VERSION 5.7 ;
  NOWIREEXTENSIONATPIN ON ;
  DIVIDERCHAR "/" ;
  BUSBITCHARS "[]" ;
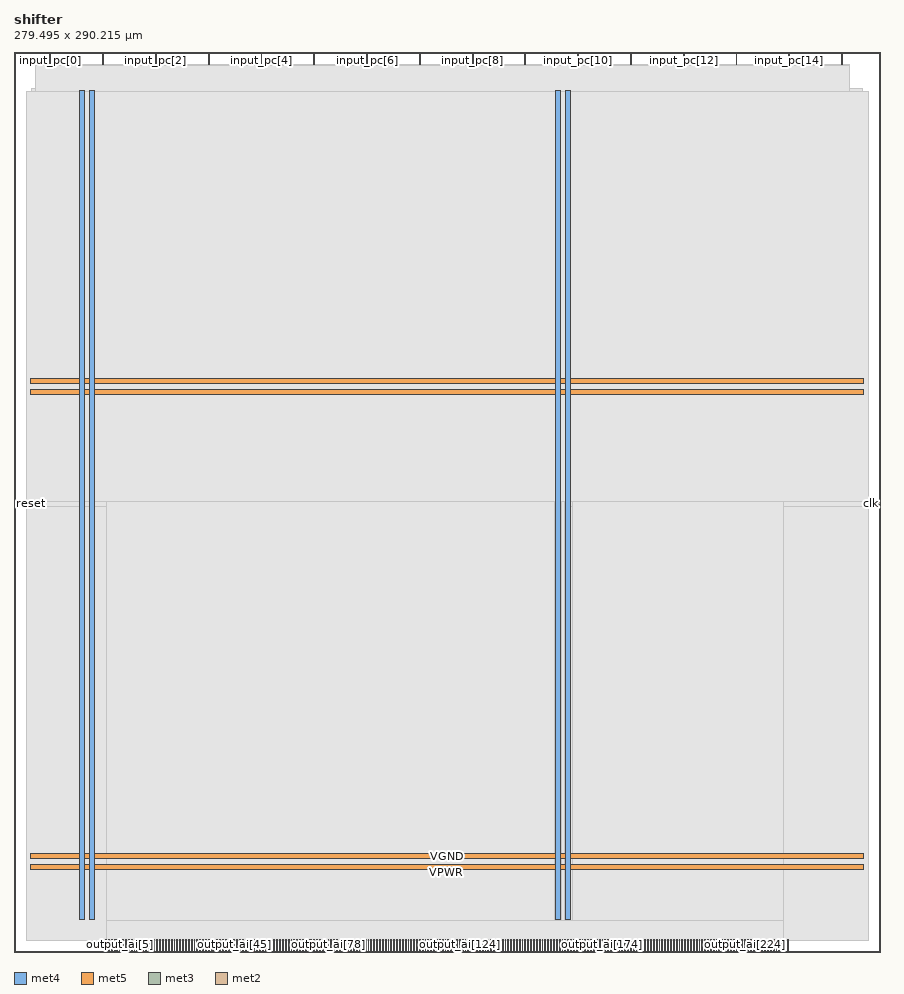
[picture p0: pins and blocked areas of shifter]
MACRO shifter
  CLASS BLOCK ;
  FOREIGN shifter ;
  ORIGIN 0.000 0.000 ;
  SIZE 279.495 BY 290.215 ;
  PIN VGND
    DIRECTION INOUT ;
    USE GROUND ;
    PORT
      LAYER met4 ;
        RECT 24.340 10.640 25.940 277.680 ;
    END
    PORT
      LAYER met4 ;
        RECT 177.940 10.640 179.540 277.680 ;
    END
    PORT
      LAYER met5 ;
        RECT 5.280 30.030 273.940 31.630 ;
    END
    PORT
      LAYER met5 ;
        RECT 5.280 183.210 273.940 184.810 ;
    END
  END VGND
  PIN VPWR
    DIRECTION INOUT ;
    USE POWER ;
    PORT
      LAYER met4 ;
        RECT 21.040 10.640 22.640 277.680 ;
    END
    PORT
      LAYER met4 ;
        RECT 174.640 10.640 176.240 277.680 ;
    END
    PORT
      LAYER met5 ;
        RECT 5.280 26.730 273.940 28.330 ;
    END
    PORT
      LAYER met5 ;
        RECT 5.280 179.910 273.940 181.510 ;
    END
  END VPWR
  PIN clk
    DIRECTION INPUT ;
    USE SIGNAL ;
    ANTENNAGATEAREA 0.852000 ;
    PORT
      LAYER met3 ;
        RECT 275.495 144.200 279.495 144.800 ;
    END
  END clk
  PIN input_pc[0]
    DIRECTION INPUT ;
    USE SIGNAL ;
    ANTENNAGATEAREA 0.213000 ;
    PORT
      LAYER met2 ;
        RECT 11.590 286.215 11.870 290.215 ;
    END
  END input_pc[0]
  PIN input_pc[10]
    DIRECTION INPUT ;
    USE SIGNAL ;
    ANTENNAGATEAREA 0.213000 ;
    PORT
      LAYER met2 ;
        RECT 181.790 286.215 182.070 290.215 ;
    END
  END input_pc[10]
  PIN input_pc[11]
    DIRECTION INPUT ;
    USE SIGNAL ;
    ANTENNAGATEAREA 0.196500 ;
    PORT
      LAYER met2 ;
        RECT 198.810 286.215 199.090 290.215 ;
    END
  END input_pc[11]
  PIN input_pc[12]
    DIRECTION INPUT ;
    USE SIGNAL ;
    ANTENNAGATEAREA 0.196500 ;
    PORT
      LAYER met2 ;
        RECT 215.830 286.215 216.110 290.215 ;
    END
  END input_pc[12]
  PIN input_pc[13]
    DIRECTION INPUT ;
    USE SIGNAL ;
    ANTENNAGATEAREA 0.196500 ;
    PORT
      LAYER met2 ;
        RECT 232.850 286.215 233.130 290.215 ;
    END
  END input_pc[13]
  PIN input_pc[14]
    DIRECTION INPUT ;
    USE SIGNAL ;
    ANTENNAGATEAREA 0.126000 ;
    PORT
      LAYER met2 ;
        RECT 249.870 286.215 250.150 290.215 ;
    END
  END input_pc[14]
  PIN input_pc[15]
    DIRECTION INPUT ;
    USE SIGNAL ;
    ANTENNAGATEAREA 0.126000 ;
    PORT
      LAYER met2 ;
        RECT 266.890 286.215 267.170 290.215 ;
    END
  END input_pc[15]
  PIN input_pc[1]
    DIRECTION INPUT ;
    USE SIGNAL ;
    ANTENNAGATEAREA 0.196500 ;
    PORT
      LAYER met2 ;
        RECT 28.610 286.215 28.890 290.215 ;
    END
  END input_pc[1]
  PIN input_pc[2]
    DIRECTION INPUT ;
    USE SIGNAL ;
    ANTENNAGATEAREA 0.126000 ;
    PORT
      LAYER met2 ;
        RECT 45.630 286.215 45.910 290.215 ;
    END
  END input_pc[2]
  PIN input_pc[3]
    DIRECTION INPUT ;
    USE SIGNAL ;
    ANTENNAGATEAREA 0.213000 ;
    PORT
      LAYER met2 ;
        RECT 62.650 286.215 62.930 290.215 ;
    END
  END input_pc[3]
  PIN input_pc[4]
    DIRECTION INPUT ;
    USE SIGNAL ;
    ANTENNAGATEAREA 0.196500 ;
    PORT
      LAYER met2 ;
        RECT 79.670 286.215 79.950 290.215 ;
    END
  END input_pc[4]
  PIN input_pc[5]
    DIRECTION INPUT ;
    USE SIGNAL ;
    ANTENNAGATEAREA 0.213000 ;
    PORT
      LAYER met2 ;
        RECT 96.690 286.215 96.970 290.215 ;
    END
  END input_pc[5]
  PIN input_pc[6]
    DIRECTION INPUT ;
    USE SIGNAL ;
    ANTENNAGATEAREA 0.213000 ;
    PORT
      LAYER met2 ;
        RECT 113.710 286.215 113.990 290.215 ;
    END
  END input_pc[6]
  PIN input_pc[7]
    DIRECTION INPUT ;
    USE SIGNAL ;
    ANTENNAGATEAREA 0.213000 ;
    PORT
      LAYER met2 ;
        RECT 130.730 286.215 131.010 290.215 ;
    END
  END input_pc[7]
  PIN input_pc[8]
    DIRECTION INPUT ;
    USE SIGNAL ;
    ANTENNAGATEAREA 0.213000 ;
    PORT
      LAYER met2 ;
        RECT 147.750 286.215 148.030 290.215 ;
    END
  END input_pc[8]
  PIN input_pc[9]
    DIRECTION INPUT ;
    USE SIGNAL ;
    ANTENNAGATEAREA 0.213000 ;
    PORT
      LAYER met2 ;
        RECT 164.770 286.215 165.050 290.215 ;
    END
  END input_pc[9]
  PIN output_ai[0]
    DIRECTION OUTPUT ;
    USE SIGNAL ;
    ANTENNADIFFAREA 0.445500 ;
    PORT
      LAYER met2 ;
        RECT 29.530 0.000 29.810 4.000 ;
    END
  END output_ai[0]
  PIN output_ai[100]
    DIRECTION OUTPUT ;
    USE SIGNAL ;
    ANTENNADIFFAREA 0.445500 ;
    PORT
      LAYER met2 ;
        RECT 121.530 0.000 121.810 4.000 ;
    END
  END output_ai[100]
  PIN output_ai[101]
    DIRECTION OUTPUT ;
    USE SIGNAL ;
    ANTENNADIFFAREA 0.445500 ;
    PORT
      LAYER met2 ;
        RECT 122.450 0.000 122.730 4.000 ;
    END
  END output_ai[101]
  PIN output_ai[102]
    DIRECTION OUTPUT ;
    USE SIGNAL ;
    ANTENNADIFFAREA 0.445500 ;
    PORT
      LAYER met2 ;
        RECT 123.370 0.000 123.650 4.000 ;
    END
  END output_ai[102]
  PIN output_ai[103]
    DIRECTION OUTPUT ;
    USE SIGNAL ;
    ANTENNADIFFAREA 0.445500 ;
    PORT
      LAYER met2 ;
        RECT 124.290 0.000 124.570 4.000 ;
    END
  END output_ai[103]
  PIN output_ai[104]
    DIRECTION OUTPUT ;
    USE SIGNAL ;
    ANTENNADIFFAREA 0.445500 ;
    PORT
      LAYER met2 ;
        RECT 125.210 0.000 125.490 4.000 ;
    END
  END output_ai[104]
  PIN output_ai[105]
    DIRECTION OUTPUT ;
    USE SIGNAL ;
    ANTENNADIFFAREA 0.445500 ;
    PORT
      LAYER met2 ;
        RECT 126.130 0.000 126.410 4.000 ;
    END
  END output_ai[105]
  PIN output_ai[106]
    DIRECTION OUTPUT ;
    USE SIGNAL ;
    ANTENNADIFFAREA 0.445500 ;
    PORT
      LAYER met2 ;
        RECT 127.050 0.000 127.330 4.000 ;
    END
  END output_ai[106]
  PIN output_ai[107]
    DIRECTION OUTPUT ;
    USE SIGNAL ;
    ANTENNADIFFAREA 0.445500 ;
    PORT
      LAYER met2 ;
        RECT 127.970 0.000 128.250 4.000 ;
    END
  END output_ai[107]
  PIN output_ai[108]
    DIRECTION OUTPUT ;
    USE SIGNAL ;
    ANTENNADIFFAREA 0.445500 ;
    PORT
      LAYER met2 ;
        RECT 128.890 0.000 129.170 4.000 ;
    END
  END output_ai[108]
  PIN output_ai[109]
    DIRECTION OUTPUT ;
    USE SIGNAL ;
    ANTENNADIFFAREA 0.445500 ;
    PORT
      LAYER met2 ;
        RECT 129.810 0.000 130.090 4.000 ;
    END
  END output_ai[109]
  PIN output_ai[10]
    DIRECTION OUTPUT ;
    USE SIGNAL ;
    ANTENNADIFFAREA 0.445500 ;
    PORT
      LAYER met2 ;
        RECT 38.730 0.000 39.010 4.000 ;
    END
  END output_ai[10]
  PIN output_ai[110]
    DIRECTION OUTPUT ;
    USE SIGNAL ;
    ANTENNADIFFAREA 0.445500 ;
    PORT
      LAYER met2 ;
        RECT 130.730 0.000 131.010 4.000 ;
    END
  END output_ai[110]
  PIN output_ai[111]
    DIRECTION OUTPUT ;
    USE SIGNAL ;
    ANTENNADIFFAREA 0.445500 ;
    PORT
      LAYER met2 ;
        RECT 131.650 0.000 131.930 4.000 ;
    END
  END output_ai[111]
  PIN output_ai[112]
    DIRECTION OUTPUT ;
    USE SIGNAL ;
    ANTENNADIFFAREA 0.445500 ;
    PORT
      LAYER met2 ;
        RECT 132.570 0.000 132.850 4.000 ;
    END
  END output_ai[112]
  PIN output_ai[113]
    DIRECTION OUTPUT ;
    USE SIGNAL ;
    ANTENNADIFFAREA 0.445500 ;
    PORT
      LAYER met2 ;
        RECT 133.490 0.000 133.770 4.000 ;
    END
  END output_ai[113]
  PIN output_ai[114]
    DIRECTION OUTPUT ;
    USE SIGNAL ;
    ANTENNADIFFAREA 0.445500 ;
    PORT
      LAYER met2 ;
        RECT 134.410 0.000 134.690 4.000 ;
    END
  END output_ai[114]
  PIN output_ai[115]
    DIRECTION OUTPUT ;
    USE SIGNAL ;
    ANTENNADIFFAREA 0.445500 ;
    PORT
      LAYER met2 ;
        RECT 135.330 0.000 135.610 4.000 ;
    END
  END output_ai[115]
  PIN output_ai[116]
    DIRECTION OUTPUT ;
    USE SIGNAL ;
    ANTENNADIFFAREA 0.445500 ;
    PORT
      LAYER met2 ;
        RECT 136.250 0.000 136.530 4.000 ;
    END
  END output_ai[116]
  PIN output_ai[117]
    DIRECTION OUTPUT ;
    USE SIGNAL ;
    ANTENNADIFFAREA 0.445500 ;
    PORT
      LAYER met2 ;
        RECT 137.170 0.000 137.450 4.000 ;
    END
  END output_ai[117]
  PIN output_ai[118]
    DIRECTION OUTPUT ;
    USE SIGNAL ;
    ANTENNADIFFAREA 0.445500 ;
    PORT
      LAYER met2 ;
        RECT 138.090 0.000 138.370 4.000 ;
    END
  END output_ai[118]
  PIN output_ai[119]
    DIRECTION OUTPUT ;
    USE SIGNAL ;
    ANTENNADIFFAREA 0.445500 ;
    PORT
      LAYER met2 ;
        RECT 139.010 0.000 139.290 4.000 ;
    END
  END output_ai[119]
  PIN output_ai[11]
    DIRECTION OUTPUT ;
    USE SIGNAL ;
    ANTENNADIFFAREA 0.445500 ;
    PORT
      LAYER met2 ;
        RECT 39.650 0.000 39.930 4.000 ;
    END
  END output_ai[11]
  PIN output_ai[120]
    DIRECTION OUTPUT ;
    USE SIGNAL ;
    ANTENNADIFFAREA 0.445500 ;
    PORT
      LAYER met2 ;
        RECT 139.930 0.000 140.210 4.000 ;
    END
  END output_ai[120]
  PIN output_ai[121]
    DIRECTION OUTPUT ;
    USE SIGNAL ;
    ANTENNADIFFAREA 0.445500 ;
    PORT
      LAYER met2 ;
        RECT 140.850 0.000 141.130 4.000 ;
    END
  END output_ai[121]
  PIN output_ai[122]
    DIRECTION OUTPUT ;
    USE SIGNAL ;
    ANTENNADIFFAREA 0.445500 ;
    PORT
      LAYER met2 ;
        RECT 141.770 0.000 142.050 4.000 ;
    END
  END output_ai[122]
  PIN output_ai[123]
    DIRECTION OUTPUT ;
    USE SIGNAL ;
    ANTENNADIFFAREA 0.445500 ;
    PORT
      LAYER met2 ;
        RECT 142.690 0.000 142.970 4.000 ;
    END
  END output_ai[123]
  PIN output_ai[124]
    DIRECTION OUTPUT ;
    USE SIGNAL ;
    ANTENNADIFFAREA 0.445500 ;
    PORT
      LAYER met2 ;
        RECT 143.610 0.000 143.890 4.000 ;
    END
  END output_ai[124]
  PIN output_ai[125]
    DIRECTION OUTPUT ;
    USE SIGNAL ;
    ANTENNADIFFAREA 0.445500 ;
    PORT
      LAYER met2 ;
        RECT 144.530 0.000 144.810 4.000 ;
    END
  END output_ai[125]
  PIN output_ai[126]
    DIRECTION OUTPUT ;
    USE SIGNAL ;
    ANTENNADIFFAREA 0.445500 ;
    PORT
      LAYER met2 ;
        RECT 145.450 0.000 145.730 4.000 ;
    END
  END output_ai[126]
  PIN output_ai[127]
    DIRECTION OUTPUT ;
    USE SIGNAL ;
    ANTENNADIFFAREA 0.445500 ;
    PORT
      LAYER met2 ;
        RECT 146.370 0.000 146.650 4.000 ;
    END
  END output_ai[127]
  PIN output_ai[128]
    DIRECTION OUTPUT ;
    USE SIGNAL ;
    ANTENNADIFFAREA 0.445500 ;
    PORT
      LAYER met2 ;
        RECT 147.290 0.000 147.570 4.000 ;
    END
  END output_ai[128]
  PIN output_ai[129]
    DIRECTION OUTPUT ;
    USE SIGNAL ;
    ANTENNADIFFAREA 0.445500 ;
    PORT
      LAYER met2 ;
        RECT 148.210 0.000 148.490 4.000 ;
    END
  END output_ai[129]
  PIN output_ai[12]
    DIRECTION OUTPUT ;
    USE SIGNAL ;
    ANTENNADIFFAREA 0.445500 ;
    PORT
      LAYER met2 ;
        RECT 40.570 0.000 40.850 4.000 ;
    END
  END output_ai[12]
  PIN output_ai[130]
    DIRECTION OUTPUT ;
    USE SIGNAL ;
    ANTENNADIFFAREA 0.445500 ;
    PORT
      LAYER met2 ;
        RECT 149.130 0.000 149.410 4.000 ;
    END
  END output_ai[130]
  PIN output_ai[131]
    DIRECTION OUTPUT ;
    USE SIGNAL ;
    ANTENNADIFFAREA 0.445500 ;
    PORT
      LAYER met2 ;
        RECT 150.050 0.000 150.330 4.000 ;
    END
  END output_ai[131]
  PIN output_ai[132]
    DIRECTION OUTPUT ;
    USE SIGNAL ;
    ANTENNADIFFAREA 0.445500 ;
    PORT
      LAYER met2 ;
        RECT 150.970 0.000 151.250 4.000 ;
    END
  END output_ai[132]
  PIN output_ai[133]
    DIRECTION OUTPUT ;
    USE SIGNAL ;
    ANTENNADIFFAREA 0.445500 ;
    PORT
      LAYER met2 ;
        RECT 151.890 0.000 152.170 4.000 ;
    END
  END output_ai[133]
  PIN output_ai[134]
    DIRECTION OUTPUT ;
    USE SIGNAL ;
    ANTENNADIFFAREA 0.445500 ;
    PORT
      LAYER met2 ;
        RECT 152.810 0.000 153.090 4.000 ;
    END
  END output_ai[134]
  PIN output_ai[135]
    DIRECTION OUTPUT ;
    USE SIGNAL ;
    ANTENNADIFFAREA 0.445500 ;
    PORT
      LAYER met2 ;
        RECT 153.730 0.000 154.010 4.000 ;
    END
  END output_ai[135]
  PIN output_ai[136]
    DIRECTION OUTPUT ;
    USE SIGNAL ;
    ANTENNADIFFAREA 0.445500 ;
    PORT
      LAYER met2 ;
        RECT 154.650 0.000 154.930 4.000 ;
    END
  END output_ai[136]
  PIN output_ai[137]
    DIRECTION OUTPUT ;
    USE SIGNAL ;
    ANTENNADIFFAREA 0.445500 ;
    PORT
      LAYER met2 ;
        RECT 155.570 0.000 155.850 4.000 ;
    END
  END output_ai[137]
  PIN output_ai[138]
    DIRECTION OUTPUT ;
    USE SIGNAL ;
    ANTENNADIFFAREA 0.445500 ;
    PORT
      LAYER met2 ;
        RECT 156.490 0.000 156.770 4.000 ;
    END
  END output_ai[138]
  PIN output_ai[139]
    DIRECTION OUTPUT ;
    USE SIGNAL ;
    ANTENNADIFFAREA 0.445500 ;
    PORT
      LAYER met2 ;
        RECT 157.410 0.000 157.690 4.000 ;
    END
  END output_ai[139]
  PIN output_ai[13]
    DIRECTION OUTPUT ;
    USE SIGNAL ;
    ANTENNADIFFAREA 0.445500 ;
    PORT
      LAYER met2 ;
        RECT 41.490 0.000 41.770 4.000 ;
    END
  END output_ai[13]
  PIN output_ai[140]
    DIRECTION OUTPUT ;
    USE SIGNAL ;
    ANTENNADIFFAREA 0.445500 ;
    PORT
      LAYER met2 ;
        RECT 158.330 0.000 158.610 4.000 ;
    END
  END output_ai[140]
  PIN output_ai[141]
    DIRECTION OUTPUT ;
    USE SIGNAL ;
    ANTENNADIFFAREA 0.445500 ;
    PORT
      LAYER met2 ;
        RECT 159.250 0.000 159.530 4.000 ;
    END
  END output_ai[141]
  PIN output_ai[142]
    DIRECTION OUTPUT ;
    USE SIGNAL ;
    ANTENNADIFFAREA 0.445500 ;
    PORT
      LAYER met2 ;
        RECT 160.170 0.000 160.450 4.000 ;
    END
  END output_ai[142]
  PIN output_ai[143]
    DIRECTION OUTPUT ;
    USE SIGNAL ;
    ANTENNADIFFAREA 0.445500 ;
    PORT
      LAYER met2 ;
        RECT 161.090 0.000 161.370 4.000 ;
    END
  END output_ai[143]
  PIN output_ai[144]
    DIRECTION OUTPUT ;
    USE SIGNAL ;
    ANTENNADIFFAREA 0.445500 ;
    PORT
      LAYER met2 ;
        RECT 162.010 0.000 162.290 4.000 ;
    END
  END output_ai[144]
  PIN output_ai[145]
    DIRECTION OUTPUT ;
    USE SIGNAL ;
    ANTENNADIFFAREA 0.445500 ;
    PORT
      LAYER met2 ;
        RECT 162.930 0.000 163.210 4.000 ;
    END
  END output_ai[145]
  PIN output_ai[146]
    DIRECTION OUTPUT ;
    USE SIGNAL ;
    ANTENNADIFFAREA 0.445500 ;
    PORT
      LAYER met2 ;
        RECT 163.850 0.000 164.130 4.000 ;
    END
  END output_ai[146]
  PIN output_ai[147]
    DIRECTION OUTPUT ;
    USE SIGNAL ;
    ANTENNADIFFAREA 0.445500 ;
    PORT
      LAYER met2 ;
        RECT 164.770 0.000 165.050 4.000 ;
    END
  END output_ai[147]
  PIN output_ai[148]
    DIRECTION OUTPUT ;
    USE SIGNAL ;
    ANTENNADIFFAREA 0.445500 ;
    PORT
      LAYER met2 ;
        RECT 165.690 0.000 165.970 4.000 ;
    END
  END output_ai[148]
  PIN output_ai[149]
    DIRECTION OUTPUT ;
    USE SIGNAL ;
    ANTENNADIFFAREA 0.445500 ;
    PORT
      LAYER met2 ;
        RECT 166.610 0.000 166.890 4.000 ;
    END
  END output_ai[149]
  PIN output_ai[14]
    DIRECTION OUTPUT ;
    USE SIGNAL ;
    ANTENNADIFFAREA 0.445500 ;
    PORT
      LAYER met2 ;
        RECT 42.410 0.000 42.690 4.000 ;
    END
  END output_ai[14]
  PIN output_ai[150]
    DIRECTION OUTPUT ;
    USE SIGNAL ;
    ANTENNADIFFAREA 0.445500 ;
    PORT
      LAYER met2 ;
        RECT 167.530 0.000 167.810 4.000 ;
    END
  END output_ai[150]
  PIN output_ai[151]
    DIRECTION OUTPUT ;
    USE SIGNAL ;
    ANTENNADIFFAREA 0.445500 ;
    PORT
      LAYER met2 ;
        RECT 168.450 0.000 168.730 4.000 ;
    END
  END output_ai[151]
  PIN output_ai[152]
    DIRECTION OUTPUT ;
    USE SIGNAL ;
    ANTENNADIFFAREA 0.445500 ;
    PORT
      LAYER met2 ;
        RECT 169.370 0.000 169.650 4.000 ;
    END
  END output_ai[152]
  PIN output_ai[153]
    DIRECTION OUTPUT ;
    USE SIGNAL ;
    ANTENNADIFFAREA 0.445500 ;
    PORT
      LAYER met2 ;
        RECT 170.290 0.000 170.570 4.000 ;
    END
  END output_ai[153]
  PIN output_ai[154]
    DIRECTION OUTPUT ;
    USE SIGNAL ;
    ANTENNADIFFAREA 0.445500 ;
    PORT
      LAYER met2 ;
        RECT 171.210 0.000 171.490 4.000 ;
    END
  END output_ai[154]
  PIN output_ai[155]
    DIRECTION OUTPUT ;
    USE SIGNAL ;
    ANTENNADIFFAREA 0.445500 ;
    PORT
      LAYER met2 ;
        RECT 172.130 0.000 172.410 4.000 ;
    END
  END output_ai[155]
  PIN output_ai[156]
    DIRECTION OUTPUT ;
    USE SIGNAL ;
    ANTENNADIFFAREA 0.445500 ;
    PORT
      LAYER met2 ;
        RECT 173.050 0.000 173.330 4.000 ;
    END
  END output_ai[156]
  PIN output_ai[157]
    DIRECTION OUTPUT ;
    USE SIGNAL ;
    ANTENNADIFFAREA 0.445500 ;
    PORT
      LAYER met2 ;
        RECT 173.970 0.000 174.250 4.000 ;
    END
  END output_ai[157]
  PIN output_ai[158]
    DIRECTION OUTPUT ;
    USE SIGNAL ;
    ANTENNADIFFAREA 0.445500 ;
    PORT
      LAYER met2 ;
        RECT 174.890 0.000 175.170 4.000 ;
    END
  END output_ai[158]
  PIN output_ai[159]
    DIRECTION OUTPUT ;
    USE SIGNAL ;
    ANTENNADIFFAREA 0.445500 ;
    PORT
      LAYER met2 ;
        RECT 175.810 0.000 176.090 4.000 ;
    END
  END output_ai[159]
  PIN output_ai[15]
    DIRECTION OUTPUT ;
    USE SIGNAL ;
    ANTENNADIFFAREA 0.445500 ;
    PORT
      LAYER met2 ;
        RECT 43.330 0.000 43.610 4.000 ;
    END
  END output_ai[15]
  PIN output_ai[160]
    DIRECTION OUTPUT ;
    USE SIGNAL ;
    ANTENNADIFFAREA 0.445500 ;
    PORT
      LAYER met2 ;
        RECT 176.730 0.000 177.010 4.000 ;
    END
  END output_ai[160]
  PIN output_ai[161]
    DIRECTION OUTPUT ;
    USE SIGNAL ;
    ANTENNADIFFAREA 0.445500 ;
    PORT
      LAYER met2 ;
        RECT 177.650 0.000 177.930 4.000 ;
    END
  END output_ai[161]
  PIN output_ai[162]
    DIRECTION OUTPUT ;
    USE SIGNAL ;
    ANTENNADIFFAREA 0.445500 ;
    PORT
      LAYER met2 ;
        RECT 178.570 0.000 178.850 4.000 ;
    END
  END output_ai[162]
  PIN output_ai[163]
    DIRECTION OUTPUT ;
    USE SIGNAL ;
    ANTENNADIFFAREA 0.445500 ;
    PORT
      LAYER met2 ;
        RECT 179.490 0.000 179.770 4.000 ;
    END
  END output_ai[163]
  PIN output_ai[164]
    DIRECTION OUTPUT ;
    USE SIGNAL ;
    ANTENNADIFFAREA 0.445500 ;
    PORT
      LAYER met2 ;
        RECT 180.410 0.000 180.690 4.000 ;
    END
  END output_ai[164]
  PIN output_ai[165]
    DIRECTION OUTPUT ;
    USE SIGNAL ;
    ANTENNADIFFAREA 0.445500 ;
    PORT
      LAYER met2 ;
        RECT 181.330 0.000 181.610 4.000 ;
    END
  END output_ai[165]
  PIN output_ai[166]
    DIRECTION OUTPUT ;
    USE SIGNAL ;
    ANTENNADIFFAREA 0.445500 ;
    PORT
      LAYER met2 ;
        RECT 182.250 0.000 182.530 4.000 ;
    END
  END output_ai[166]
  PIN output_ai[167]
    DIRECTION OUTPUT ;
    USE SIGNAL ;
    ANTENNADIFFAREA 0.445500 ;
    PORT
      LAYER met2 ;
        RECT 183.170 0.000 183.450 4.000 ;
    END
  END output_ai[167]
  PIN output_ai[168]
    DIRECTION OUTPUT ;
    USE SIGNAL ;
    ANTENNADIFFAREA 0.445500 ;
    PORT
      LAYER met2 ;
        RECT 184.090 0.000 184.370 4.000 ;
    END
  END output_ai[168]
  PIN output_ai[169]
    DIRECTION OUTPUT ;
    USE SIGNAL ;
    ANTENNADIFFAREA 0.445500 ;
    PORT
      LAYER met2 ;
        RECT 185.010 0.000 185.290 4.000 ;
    END
  END output_ai[169]
  PIN output_ai[16]
    DIRECTION OUTPUT ;
    USE SIGNAL ;
    ANTENNADIFFAREA 0.445500 ;
    PORT
      LAYER met2 ;
        RECT 44.250 0.000 44.530 4.000 ;
    END
  END output_ai[16]
  PIN output_ai[170]
    DIRECTION OUTPUT ;
    USE SIGNAL ;
    ANTENNADIFFAREA 0.445500 ;
    PORT
      LAYER met2 ;
        RECT 185.930 0.000 186.210 4.000 ;
    END
  END output_ai[170]
  PIN output_ai[171]
    DIRECTION OUTPUT ;
    USE SIGNAL ;
    ANTENNADIFFAREA 0.445500 ;
    PORT
      LAYER met2 ;
        RECT 186.850 0.000 187.130 4.000 ;
    END
  END output_ai[171]
  PIN output_ai[172]
    DIRECTION OUTPUT ;
    USE SIGNAL ;
    ANTENNADIFFAREA 0.445500 ;
    PORT
      LAYER met2 ;
        RECT 187.770 0.000 188.050 4.000 ;
    END
  END output_ai[172]
  PIN output_ai[173]
    DIRECTION OUTPUT ;
    USE SIGNAL ;
    ANTENNADIFFAREA 0.445500 ;
    PORT
      LAYER met2 ;
        RECT 188.690 0.000 188.970 4.000 ;
    END
  END output_ai[173]
  PIN output_ai[174]
    DIRECTION OUTPUT ;
    USE SIGNAL ;
    ANTENNADIFFAREA 0.445500 ;
    PORT
      LAYER met2 ;
        RECT 189.610 0.000 189.890 4.000 ;
    END
  END output_ai[174]
  PIN output_ai[175]
    DIRECTION OUTPUT ;
    USE SIGNAL ;
    ANTENNADIFFAREA 0.445500 ;
    PORT
      LAYER met2 ;
        RECT 190.530 0.000 190.810 4.000 ;
    END
  END output_ai[175]
  PIN output_ai[176]
    DIRECTION OUTPUT ;
    USE SIGNAL ;
    ANTENNADIFFAREA 0.445500 ;
    PORT
      LAYER met2 ;
        RECT 191.450 0.000 191.730 4.000 ;
    END
  END output_ai[176]
  PIN output_ai[177]
    DIRECTION OUTPUT ;
    USE SIGNAL ;
    ANTENNADIFFAREA 0.445500 ;
    PORT
      LAYER met2 ;
        RECT 192.370 0.000 192.650 4.000 ;
    END
  END output_ai[177]
  PIN output_ai[178]
    DIRECTION OUTPUT ;
    USE SIGNAL ;
    ANTENNADIFFAREA 0.445500 ;
    PORT
      LAYER met2 ;
        RECT 193.290 0.000 193.570 4.000 ;
    END
  END output_ai[178]
  PIN output_ai[179]
    DIRECTION OUTPUT ;
    USE SIGNAL ;
    ANTENNADIFFAREA 0.445500 ;
    PORT
      LAYER met2 ;
        RECT 194.210 0.000 194.490 4.000 ;
    END
  END output_ai[179]
  PIN output_ai[17]
    DIRECTION OUTPUT ;
    USE SIGNAL ;
    ANTENNADIFFAREA 0.445500 ;
    PORT
      LAYER met2 ;
        RECT 45.170 0.000 45.450 4.000 ;
    END
  END output_ai[17]
  PIN output_ai[180]
    DIRECTION OUTPUT ;
    USE SIGNAL ;
    ANTENNADIFFAREA 0.445500 ;
    PORT
      LAYER met2 ;
        RECT 195.130 0.000 195.410 4.000 ;
    END
  END output_ai[180]
  PIN output_ai[181]
    DIRECTION OUTPUT ;
    USE SIGNAL ;
    ANTENNADIFFAREA 0.445500 ;
    PORT
      LAYER met2 ;
        RECT 196.050 0.000 196.330 4.000 ;
    END
  END output_ai[181]
  PIN output_ai[182]
    DIRECTION OUTPUT ;
    USE SIGNAL ;
    ANTENNADIFFAREA 0.445500 ;
    PORT
      LAYER met2 ;
        RECT 196.970 0.000 197.250 4.000 ;
    END
  END output_ai[182]
  PIN output_ai[183]
    DIRECTION OUTPUT ;
    USE SIGNAL ;
    ANTENNADIFFAREA 0.445500 ;
    PORT
      LAYER met2 ;
        RECT 197.890 0.000 198.170 4.000 ;
    END
  END output_ai[183]
  PIN output_ai[184]
    DIRECTION OUTPUT ;
    USE SIGNAL ;
    ANTENNADIFFAREA 0.445500 ;
    PORT
      LAYER met2 ;
        RECT 198.810 0.000 199.090 4.000 ;
    END
  END output_ai[184]
  PIN output_ai[185]
    DIRECTION OUTPUT ;
    USE SIGNAL ;
    ANTENNADIFFAREA 0.445500 ;
    PORT
      LAYER met2 ;
        RECT 199.730 0.000 200.010 4.000 ;
    END
  END output_ai[185]
  PIN output_ai[186]
    DIRECTION OUTPUT ;
    USE SIGNAL ;
    ANTENNADIFFAREA 0.445500 ;
    PORT
      LAYER met2 ;
        RECT 200.650 0.000 200.930 4.000 ;
    END
  END output_ai[186]
  PIN output_ai[187]
    DIRECTION OUTPUT ;
    USE SIGNAL ;
    ANTENNADIFFAREA 0.445500 ;
    PORT
      LAYER met2 ;
        RECT 201.570 0.000 201.850 4.000 ;
    END
  END output_ai[187]
  PIN output_ai[188]
    DIRECTION OUTPUT ;
    USE SIGNAL ;
    ANTENNADIFFAREA 0.445500 ;
    PORT
      LAYER met2 ;
        RECT 202.490 0.000 202.770 4.000 ;
    END
  END output_ai[188]
  PIN output_ai[189]
    DIRECTION OUTPUT ;
    USE SIGNAL ;
    ANTENNADIFFAREA 0.445500 ;
    PORT
      LAYER met2 ;
        RECT 203.410 0.000 203.690 4.000 ;
    END
  END output_ai[189]
  PIN output_ai[18]
    DIRECTION OUTPUT ;
    USE SIGNAL ;
    ANTENNADIFFAREA 0.445500 ;
    PORT
      LAYER met2 ;
        RECT 46.090 0.000 46.370 4.000 ;
    END
  END output_ai[18]
  PIN output_ai[190]
    DIRECTION OUTPUT ;
    USE SIGNAL ;
    ANTENNADIFFAREA 0.445500 ;
    PORT
      LAYER met2 ;
        RECT 204.330 0.000 204.610 4.000 ;
    END
  END output_ai[190]
  PIN output_ai[191]
    DIRECTION OUTPUT ;
    USE SIGNAL ;
    ANTENNADIFFAREA 0.445500 ;
    PORT
      LAYER met2 ;
        RECT 205.250 0.000 205.530 4.000 ;
    END
  END output_ai[191]
  PIN output_ai[192]
    DIRECTION OUTPUT ;
    USE SIGNAL ;
    ANTENNADIFFAREA 0.445500 ;
    PORT
      LAYER met2 ;
        RECT 206.170 0.000 206.450 4.000 ;
    END
  END output_ai[192]
  PIN output_ai[193]
    DIRECTION OUTPUT ;
    USE SIGNAL ;
    ANTENNADIFFAREA 0.445500 ;
    PORT
      LAYER met2 ;
        RECT 207.090 0.000 207.370 4.000 ;
    END
  END output_ai[193]
  PIN output_ai[194]
    DIRECTION OUTPUT ;
    USE SIGNAL ;
    ANTENNADIFFAREA 0.445500 ;
    PORT
      LAYER met2 ;
        RECT 208.010 0.000 208.290 4.000 ;
    END
  END output_ai[194]
  PIN output_ai[195]
    DIRECTION OUTPUT ;
    USE SIGNAL ;
    ANTENNADIFFAREA 0.445500 ;
    PORT
      LAYER met2 ;
        RECT 208.930 0.000 209.210 4.000 ;
    END
  END output_ai[195]
  PIN output_ai[196]
    DIRECTION OUTPUT ;
    USE SIGNAL ;
    ANTENNADIFFAREA 0.445500 ;
    PORT
      LAYER met2 ;
        RECT 209.850 0.000 210.130 4.000 ;
    END
  END output_ai[196]
  PIN output_ai[197]
    DIRECTION OUTPUT ;
    USE SIGNAL ;
    ANTENNADIFFAREA 0.445500 ;
    PORT
      LAYER met2 ;
        RECT 210.770 0.000 211.050 4.000 ;
    END
  END output_ai[197]
  PIN output_ai[198]
    DIRECTION OUTPUT ;
    USE SIGNAL ;
    ANTENNADIFFAREA 0.445500 ;
    PORT
      LAYER met2 ;
        RECT 211.690 0.000 211.970 4.000 ;
    END
  END output_ai[198]
  PIN output_ai[199]
    DIRECTION OUTPUT ;
    USE SIGNAL ;
    ANTENNADIFFAREA 0.445500 ;
    PORT
      LAYER met2 ;
        RECT 212.610 0.000 212.890 4.000 ;
    END
  END output_ai[199]
  PIN output_ai[19]
    DIRECTION OUTPUT ;
    USE SIGNAL ;
    ANTENNADIFFAREA 0.445500 ;
    PORT
      LAYER met2 ;
        RECT 47.010 0.000 47.290 4.000 ;
    END
  END output_ai[19]
  PIN output_ai[1]
    DIRECTION OUTPUT ;
    USE SIGNAL ;
    ANTENNADIFFAREA 0.445500 ;
    PORT
      LAYER met2 ;
        RECT 30.450 0.000 30.730 4.000 ;
    END
  END output_ai[1]
  PIN output_ai[200]
    DIRECTION OUTPUT ;
    USE SIGNAL ;
    ANTENNADIFFAREA 0.445500 ;
    PORT
      LAYER met2 ;
        RECT 213.530 0.000 213.810 4.000 ;
    END
  END output_ai[200]
  PIN output_ai[201]
    DIRECTION OUTPUT ;
    USE SIGNAL ;
    ANTENNADIFFAREA 0.445500 ;
    PORT
      LAYER met2 ;
        RECT 214.450 0.000 214.730 4.000 ;
    END
  END output_ai[201]
  PIN output_ai[202]
    DIRECTION OUTPUT ;
    USE SIGNAL ;
    ANTENNADIFFAREA 0.445500 ;
    PORT
      LAYER met2 ;
        RECT 215.370 0.000 215.650 4.000 ;
    END
  END output_ai[202]
  PIN output_ai[203]
    DIRECTION OUTPUT ;
    USE SIGNAL ;
    ANTENNADIFFAREA 0.445500 ;
    PORT
      LAYER met2 ;
        RECT 216.290 0.000 216.570 4.000 ;
    END
  END output_ai[203]
  PIN output_ai[204]
    DIRECTION OUTPUT ;
    USE SIGNAL ;
    ANTENNADIFFAREA 0.445500 ;
    PORT
      LAYER met2 ;
        RECT 217.210 0.000 217.490 4.000 ;
    END
  END output_ai[204]
  PIN output_ai[205]
    DIRECTION OUTPUT ;
    USE SIGNAL ;
    ANTENNADIFFAREA 0.445500 ;
    PORT
      LAYER met2 ;
        RECT 218.130 0.000 218.410 4.000 ;
    END
  END output_ai[205]
  PIN output_ai[206]
    DIRECTION OUTPUT ;
    USE SIGNAL ;
    ANTENNADIFFAREA 0.445500 ;
    PORT
      LAYER met2 ;
        RECT 219.050 0.000 219.330 4.000 ;
    END
  END output_ai[206]
  PIN output_ai[207]
    DIRECTION OUTPUT ;
    USE SIGNAL ;
    ANTENNADIFFAREA 0.445500 ;
    PORT
      LAYER met2 ;
        RECT 219.970 0.000 220.250 4.000 ;
    END
  END output_ai[207]
  PIN output_ai[208]
    DIRECTION OUTPUT ;
    USE SIGNAL ;
    ANTENNADIFFAREA 0.445500 ;
    PORT
      LAYER met2 ;
        RECT 220.890 0.000 221.170 4.000 ;
    END
  END output_ai[208]
  PIN output_ai[209]
    DIRECTION OUTPUT ;
    USE SIGNAL ;
    ANTENNADIFFAREA 0.445500 ;
    PORT
      LAYER met2 ;
        RECT 221.810 0.000 222.090 4.000 ;
    END
  END output_ai[209]
  PIN output_ai[20]
    DIRECTION OUTPUT ;
    USE SIGNAL ;
    ANTENNADIFFAREA 0.445500 ;
    PORT
      LAYER met2 ;
        RECT 47.930 0.000 48.210 4.000 ;
    END
  END output_ai[20]
  PIN output_ai[210]
    DIRECTION OUTPUT ;
    USE SIGNAL ;
    ANTENNADIFFAREA 0.445500 ;
    PORT
      LAYER met2 ;
        RECT 222.730 0.000 223.010 4.000 ;
    END
  END output_ai[210]
  PIN output_ai[211]
    DIRECTION OUTPUT ;
    USE SIGNAL ;
    ANTENNADIFFAREA 0.445500 ;
    PORT
      LAYER met2 ;
        RECT 223.650 0.000 223.930 4.000 ;
    END
  END output_ai[211]
  PIN output_ai[212]
    DIRECTION OUTPUT ;
    USE SIGNAL ;
    ANTENNADIFFAREA 0.445500 ;
    PORT
      LAYER met2 ;
        RECT 224.570 0.000 224.850 4.000 ;
    END
  END output_ai[212]
  PIN output_ai[213]
    DIRECTION OUTPUT ;
    USE SIGNAL ;
    ANTENNADIFFAREA 0.445500 ;
    PORT
      LAYER met2 ;
        RECT 225.490 0.000 225.770 4.000 ;
    END
  END output_ai[213]
  PIN output_ai[214]
    DIRECTION OUTPUT ;
    USE SIGNAL ;
    ANTENNADIFFAREA 0.445500 ;
    PORT
      LAYER met2 ;
        RECT 226.410 0.000 226.690 4.000 ;
    END
  END output_ai[214]
  PIN output_ai[215]
    DIRECTION OUTPUT ;
    USE SIGNAL ;
    ANTENNADIFFAREA 0.445500 ;
    PORT
      LAYER met2 ;
        RECT 227.330 0.000 227.610 4.000 ;
    END
  END output_ai[215]
  PIN output_ai[216]
    DIRECTION OUTPUT ;
    USE SIGNAL ;
    ANTENNADIFFAREA 0.445500 ;
    PORT
      LAYER met2 ;
        RECT 228.250 0.000 228.530 4.000 ;
    END
  END output_ai[216]
  PIN output_ai[217]
    DIRECTION OUTPUT ;
    USE SIGNAL ;
    ANTENNADIFFAREA 0.445500 ;
    PORT
      LAYER met2 ;
        RECT 229.170 0.000 229.450 4.000 ;
    END
  END output_ai[217]
  PIN output_ai[218]
    DIRECTION OUTPUT ;
    USE SIGNAL ;
    ANTENNADIFFAREA 0.445500 ;
    PORT
      LAYER met2 ;
        RECT 230.090 0.000 230.370 4.000 ;
    END
  END output_ai[218]
  PIN output_ai[219]
    DIRECTION OUTPUT ;
    USE SIGNAL ;
    ANTENNADIFFAREA 0.445500 ;
    PORT
      LAYER met2 ;
        RECT 231.010 0.000 231.290 4.000 ;
    END
  END output_ai[219]
  PIN output_ai[21]
    DIRECTION OUTPUT ;
    USE SIGNAL ;
    ANTENNADIFFAREA 0.445500 ;
    PORT
      LAYER met2 ;
        RECT 48.850 0.000 49.130 4.000 ;
    END
  END output_ai[21]
  PIN output_ai[220]
    DIRECTION OUTPUT ;
    USE SIGNAL ;
    ANTENNADIFFAREA 0.445500 ;
    PORT
      LAYER met2 ;
        RECT 231.930 0.000 232.210 4.000 ;
    END
  END output_ai[220]
  PIN output_ai[221]
    DIRECTION OUTPUT ;
    USE SIGNAL ;
    ANTENNADIFFAREA 0.445500 ;
    PORT
      LAYER met2 ;
        RECT 232.850 0.000 233.130 4.000 ;
    END
  END output_ai[221]
  PIN output_ai[222]
    DIRECTION OUTPUT ;
    USE SIGNAL ;
    ANTENNADIFFAREA 0.445500 ;
    PORT
      LAYER met2 ;
        RECT 233.770 0.000 234.050 4.000 ;
    END
  END output_ai[222]
  PIN output_ai[223]
    DIRECTION OUTPUT ;
    USE SIGNAL ;
    ANTENNADIFFAREA 0.445500 ;
    PORT
      LAYER met2 ;
        RECT 234.690 0.000 234.970 4.000 ;
    END
  END output_ai[223]
  PIN output_ai[224]
    DIRECTION OUTPUT ;
    USE SIGNAL ;
    ANTENNADIFFAREA 0.445500 ;
    PORT
      LAYER met2 ;
        RECT 235.610 0.000 235.890 4.000 ;
    END
  END output_ai[224]
  PIN output_ai[225]
    DIRECTION OUTPUT ;
    USE SIGNAL ;
    ANTENNADIFFAREA 0.445500 ;
    PORT
      LAYER met2 ;
        RECT 236.530 0.000 236.810 4.000 ;
    END
  END output_ai[225]
  PIN output_ai[226]
    DIRECTION OUTPUT ;
    USE SIGNAL ;
    ANTENNADIFFAREA 0.445500 ;
    PORT
      LAYER met2 ;
        RECT 237.450 0.000 237.730 4.000 ;
    END
  END output_ai[226]
  PIN output_ai[227]
    DIRECTION OUTPUT ;
    USE SIGNAL ;
    ANTENNADIFFAREA 0.445500 ;
    PORT
      LAYER met2 ;
        RECT 238.370 0.000 238.650 4.000 ;
    END
  END output_ai[227]
  PIN output_ai[228]
    DIRECTION OUTPUT ;
    USE SIGNAL ;
    ANTENNADIFFAREA 0.445500 ;
    PORT
      LAYER met2 ;
        RECT 239.290 0.000 239.570 4.000 ;
    END
  END output_ai[228]
  PIN output_ai[229]
    DIRECTION OUTPUT ;
    USE SIGNAL ;
    ANTENNADIFFAREA 0.445500 ;
    PORT
      LAYER met2 ;
        RECT 240.210 0.000 240.490 4.000 ;
    END
  END output_ai[229]
  PIN output_ai[22]
    DIRECTION OUTPUT ;
    USE SIGNAL ;
    ANTENNADIFFAREA 0.445500 ;
    PORT
      LAYER met2 ;
        RECT 49.770 0.000 50.050 4.000 ;
    END
  END output_ai[22]
  PIN output_ai[230]
    DIRECTION OUTPUT ;
    USE SIGNAL ;
    ANTENNADIFFAREA 0.445500 ;
    PORT
      LAYER met2 ;
        RECT 241.130 0.000 241.410 4.000 ;
    END
  END output_ai[230]
  PIN output_ai[231]
    DIRECTION OUTPUT ;
    USE SIGNAL ;
    ANTENNADIFFAREA 0.445500 ;
    PORT
      LAYER met2 ;
        RECT 242.050 0.000 242.330 4.000 ;
    END
  END output_ai[231]
  PIN output_ai[232]
    DIRECTION OUTPUT ;
    USE SIGNAL ;
    ANTENNADIFFAREA 0.445500 ;
    PORT
      LAYER met2 ;
        RECT 242.970 0.000 243.250 4.000 ;
    END
  END output_ai[232]
  PIN output_ai[233]
    DIRECTION OUTPUT ;
    USE SIGNAL ;
    ANTENNADIFFAREA 0.445500 ;
    PORT
      LAYER met2 ;
        RECT 243.890 0.000 244.170 4.000 ;
    END
  END output_ai[233]
  PIN output_ai[234]
    DIRECTION OUTPUT ;
    USE SIGNAL ;
    ANTENNADIFFAREA 0.445500 ;
    PORT
      LAYER met2 ;
        RECT 244.810 0.000 245.090 4.000 ;
    END
  END output_ai[234]
  PIN output_ai[235]
    DIRECTION OUTPUT ;
    USE SIGNAL ;
    ANTENNADIFFAREA 0.445500 ;
    PORT
      LAYER met2 ;
        RECT 245.730 0.000 246.010 4.000 ;
    END
  END output_ai[235]
  PIN output_ai[236]
    DIRECTION OUTPUT ;
    USE SIGNAL ;
    ANTENNADIFFAREA 0.445500 ;
    PORT
      LAYER met2 ;
        RECT 246.650 0.000 246.930 4.000 ;
    END
  END output_ai[236]
  PIN output_ai[237]
    DIRECTION OUTPUT ;
    USE SIGNAL ;
    ANTENNADIFFAREA 0.445500 ;
    PORT
      LAYER met2 ;
        RECT 247.570 0.000 247.850 4.000 ;
    END
  END output_ai[237]
  PIN output_ai[238]
    DIRECTION OUTPUT ;
    USE SIGNAL ;
    ANTENNADIFFAREA 0.445500 ;
    PORT
      LAYER met2 ;
        RECT 248.490 0.000 248.770 4.000 ;
    END
  END output_ai[238]
  PIN output_ai[239]
    DIRECTION OUTPUT ;
    USE SIGNAL ;
    ANTENNADIFFAREA 0.445500 ;
    PORT
      LAYER met2 ;
        RECT 249.410 0.000 249.690 4.000 ;
    END
  END output_ai[239]
  PIN output_ai[23]
    DIRECTION OUTPUT ;
    USE SIGNAL ;
    ANTENNADIFFAREA 0.445500 ;
    PORT
      LAYER met2 ;
        RECT 50.690 0.000 50.970 4.000 ;
    END
  END output_ai[23]
  PIN output_ai[24]
    DIRECTION OUTPUT ;
    USE SIGNAL ;
    ANTENNADIFFAREA 0.445500 ;
    PORT
      LAYER met2 ;
        RECT 51.610 0.000 51.890 4.000 ;
    END
  END output_ai[24]
  PIN output_ai[25]
    DIRECTION OUTPUT ;
    USE SIGNAL ;
    ANTENNADIFFAREA 0.445500 ;
    PORT
      LAYER met2 ;
        RECT 52.530 0.000 52.810 4.000 ;
    END
  END output_ai[25]
  PIN output_ai[26]
    DIRECTION OUTPUT ;
    USE SIGNAL ;
    ANTENNADIFFAREA 0.445500 ;
    PORT
      LAYER met2 ;
        RECT 53.450 0.000 53.730 4.000 ;
    END
  END output_ai[26]
  PIN output_ai[27]
    DIRECTION OUTPUT ;
    USE SIGNAL ;
    ANTENNADIFFAREA 0.445500 ;
    PORT
      LAYER met2 ;
        RECT 54.370 0.000 54.650 4.000 ;
    END
  END output_ai[27]
  PIN output_ai[28]
    DIRECTION OUTPUT ;
    USE SIGNAL ;
    ANTENNADIFFAREA 0.445500 ;
    PORT
      LAYER met2 ;
        RECT 55.290 0.000 55.570 4.000 ;
    END
  END output_ai[28]
  PIN output_ai[29]
    DIRECTION OUTPUT ;
    USE SIGNAL ;
    ANTENNADIFFAREA 0.445500 ;
    PORT
      LAYER met2 ;
        RECT 56.210 0.000 56.490 4.000 ;
    END
  END output_ai[29]
  PIN output_ai[2]
    DIRECTION OUTPUT ;
    USE SIGNAL ;
    ANTENNADIFFAREA 0.445500 ;
    PORT
      LAYER met2 ;
        RECT 31.370 0.000 31.650 4.000 ;
    END
  END output_ai[2]
  PIN output_ai[30]
    DIRECTION OUTPUT ;
    USE SIGNAL ;
    ANTENNADIFFAREA 0.445500 ;
    PORT
      LAYER met2 ;
        RECT 57.130 0.000 57.410 4.000 ;
    END
  END output_ai[30]
  PIN output_ai[31]
    DIRECTION OUTPUT ;
    USE SIGNAL ;
    ANTENNADIFFAREA 0.445500 ;
    PORT
      LAYER met2 ;
        RECT 58.050 0.000 58.330 4.000 ;
    END
  END output_ai[31]
  PIN output_ai[32]
    DIRECTION OUTPUT ;
    USE SIGNAL ;
    ANTENNADIFFAREA 0.445500 ;
    PORT
      LAYER met2 ;
        RECT 58.970 0.000 59.250 4.000 ;
    END
  END output_ai[32]
  PIN output_ai[33]
    DIRECTION OUTPUT ;
    USE SIGNAL ;
    ANTENNADIFFAREA 0.445500 ;
    PORT
      LAYER met2 ;
        RECT 59.890 0.000 60.170 4.000 ;
    END
  END output_ai[33]
  PIN output_ai[34]
    DIRECTION OUTPUT ;
    USE SIGNAL ;
    ANTENNADIFFAREA 0.445500 ;
    PORT
      LAYER met2 ;
        RECT 60.810 0.000 61.090 4.000 ;
    END
  END output_ai[34]
  PIN output_ai[35]
    DIRECTION OUTPUT ;
    USE SIGNAL ;
    ANTENNADIFFAREA 0.445500 ;
    PORT
      LAYER met2 ;
        RECT 61.730 0.000 62.010 4.000 ;
    END
  END output_ai[35]
  PIN output_ai[36]
    DIRECTION OUTPUT ;
    USE SIGNAL ;
    ANTENNADIFFAREA 0.445500 ;
    PORT
      LAYER met2 ;
        RECT 62.650 0.000 62.930 4.000 ;
    END
  END output_ai[36]
  PIN output_ai[37]
    DIRECTION OUTPUT ;
    USE SIGNAL ;
    ANTENNADIFFAREA 0.445500 ;
    PORT
      LAYER met2 ;
        RECT 63.570 0.000 63.850 4.000 ;
    END
  END output_ai[37]
  PIN output_ai[38]
    DIRECTION OUTPUT ;
    USE SIGNAL ;
    ANTENNADIFFAREA 0.445500 ;
    PORT
      LAYER met2 ;
        RECT 64.490 0.000 64.770 4.000 ;
    END
  END output_ai[38]
  PIN output_ai[39]
    DIRECTION OUTPUT ;
    USE SIGNAL ;
    ANTENNADIFFAREA 0.445500 ;
    PORT
      LAYER met2 ;
        RECT 65.410 0.000 65.690 4.000 ;
    END
  END output_ai[39]
  PIN output_ai[3]
    DIRECTION OUTPUT ;
    USE SIGNAL ;
    ANTENNADIFFAREA 0.445500 ;
    PORT
      LAYER met2 ;
        RECT 32.290 0.000 32.570 4.000 ;
    END
  END output_ai[3]
  PIN output_ai[40]
    DIRECTION OUTPUT ;
    USE SIGNAL ;
    ANTENNADIFFAREA 0.445500 ;
    PORT
      LAYER met2 ;
        RECT 66.330 0.000 66.610 4.000 ;
    END
  END output_ai[40]
  PIN output_ai[41]
    DIRECTION OUTPUT ;
    USE SIGNAL ;
    ANTENNADIFFAREA 0.445500 ;
    PORT
      LAYER met2 ;
        RECT 67.250 0.000 67.530 4.000 ;
    END
  END output_ai[41]
  PIN output_ai[42]
    DIRECTION OUTPUT ;
    USE SIGNAL ;
    ANTENNADIFFAREA 0.445500 ;
    PORT
      LAYER met2 ;
        RECT 68.170 0.000 68.450 4.000 ;
    END
  END output_ai[42]
  PIN output_ai[43]
    DIRECTION OUTPUT ;
    USE SIGNAL ;
    ANTENNADIFFAREA 0.445500 ;
    PORT
      LAYER met2 ;
        RECT 69.090 0.000 69.370 4.000 ;
    END
  END output_ai[43]
  PIN output_ai[44]
    DIRECTION OUTPUT ;
    USE SIGNAL ;
    ANTENNADIFFAREA 0.445500 ;
    PORT
      LAYER met2 ;
        RECT 70.010 0.000 70.290 4.000 ;
    END
  END output_ai[44]
  PIN output_ai[45]
    DIRECTION OUTPUT ;
    USE SIGNAL ;
    ANTENNADIFFAREA 0.445500 ;
    PORT
      LAYER met2 ;
        RECT 70.930 0.000 71.210 4.000 ;
    END
  END output_ai[45]
  PIN output_ai[46]
    DIRECTION OUTPUT ;
    USE SIGNAL ;
    ANTENNADIFFAREA 0.445500 ;
    PORT
      LAYER met2 ;
        RECT 71.850 0.000 72.130 4.000 ;
    END
  END output_ai[46]
  PIN output_ai[47]
    DIRECTION OUTPUT ;
    USE SIGNAL ;
    ANTENNADIFFAREA 0.445500 ;
    PORT
      LAYER met2 ;
        RECT 72.770 0.000 73.050 4.000 ;
    END
  END output_ai[47]
  PIN output_ai[48]
    DIRECTION OUTPUT ;
    USE SIGNAL ;
    ANTENNADIFFAREA 0.445500 ;
    PORT
      LAYER met2 ;
        RECT 73.690 0.000 73.970 4.000 ;
    END
  END output_ai[48]
  PIN output_ai[49]
    DIRECTION OUTPUT ;
    USE SIGNAL ;
    ANTENNADIFFAREA 0.445500 ;
    PORT
      LAYER met2 ;
        RECT 74.610 0.000 74.890 4.000 ;
    END
  END output_ai[49]
  PIN output_ai[4]
    DIRECTION OUTPUT ;
    USE SIGNAL ;
    ANTENNADIFFAREA 0.445500 ;
    PORT
      LAYER met2 ;
        RECT 33.210 0.000 33.490 4.000 ;
    END
  END output_ai[4]
  PIN output_ai[50]
    DIRECTION OUTPUT ;
    USE SIGNAL ;
    ANTENNADIFFAREA 0.445500 ;
    PORT
      LAYER met2 ;
        RECT 75.530 0.000 75.810 4.000 ;
    END
  END output_ai[50]
  PIN output_ai[51]
    DIRECTION OUTPUT ;
    USE SIGNAL ;
    ANTENNADIFFAREA 0.445500 ;
    PORT
      LAYER met2 ;
        RECT 76.450 0.000 76.730 4.000 ;
    END
  END output_ai[51]
  PIN output_ai[52]
    DIRECTION OUTPUT ;
    USE SIGNAL ;
    ANTENNADIFFAREA 0.445500 ;
    PORT
      LAYER met2 ;
        RECT 77.370 0.000 77.650 4.000 ;
    END
  END output_ai[52]
  PIN output_ai[53]
    DIRECTION OUTPUT ;
    USE SIGNAL ;
    ANTENNADIFFAREA 0.445500 ;
    PORT
      LAYER met2 ;
        RECT 78.290 0.000 78.570 4.000 ;
    END
  END output_ai[53]
  PIN output_ai[54]
    DIRECTION OUTPUT ;
    USE SIGNAL ;
    ANTENNADIFFAREA 0.445500 ;
    PORT
      LAYER met2 ;
        RECT 79.210 0.000 79.490 4.000 ;
    END
  END output_ai[54]
  PIN output_ai[55]
    DIRECTION OUTPUT ;
    USE SIGNAL ;
    ANTENNADIFFAREA 0.445500 ;
    PORT
      LAYER met2 ;
        RECT 80.130 0.000 80.410 4.000 ;
    END
  END output_ai[55]
  PIN output_ai[56]
    DIRECTION OUTPUT ;
    USE SIGNAL ;
    ANTENNADIFFAREA 0.445500 ;
    PORT
      LAYER met2 ;
        RECT 81.050 0.000 81.330 4.000 ;
    END
  END output_ai[56]
  PIN output_ai[57]
    DIRECTION OUTPUT ;
    USE SIGNAL ;
    ANTENNADIFFAREA 0.445500 ;
    PORT
      LAYER met2 ;
        RECT 81.970 0.000 82.250 4.000 ;
    END
  END output_ai[57]
  PIN output_ai[58]
    DIRECTION OUTPUT ;
    USE SIGNAL ;
    ANTENNADIFFAREA 0.445500 ;
    PORT
      LAYER met2 ;
        RECT 82.890 0.000 83.170 4.000 ;
    END
  END output_ai[58]
  PIN output_ai[59]
    DIRECTION OUTPUT ;
    USE SIGNAL ;
    ANTENNADIFFAREA 0.445500 ;
    PORT
      LAYER met2 ;
        RECT 83.810 0.000 84.090 4.000 ;
    END
  END output_ai[59]
  PIN output_ai[5]
    DIRECTION OUTPUT ;
    USE SIGNAL ;
    ANTENNADIFFAREA 0.445500 ;
    PORT
      LAYER met2 ;
        RECT 34.130 0.000 34.410 4.000 ;
    END
  END output_ai[5]
  PIN output_ai[60]
    DIRECTION OUTPUT ;
    USE SIGNAL ;
    ANTENNADIFFAREA 0.445500 ;
    PORT
      LAYER met2 ;
        RECT 84.730 0.000 85.010 4.000 ;
    END
  END output_ai[60]
  PIN output_ai[61]
    DIRECTION OUTPUT ;
    USE SIGNAL ;
    ANTENNADIFFAREA 0.445500 ;
    PORT
      LAYER met2 ;
        RECT 85.650 0.000 85.930 4.000 ;
    END
  END output_ai[61]
  PIN output_ai[62]
    DIRECTION OUTPUT ;
    USE SIGNAL ;
    ANTENNADIFFAREA 0.445500 ;
    PORT
      LAYER met2 ;
        RECT 86.570 0.000 86.850 4.000 ;
    END
  END output_ai[62]
  PIN output_ai[63]
    DIRECTION OUTPUT ;
    USE SIGNAL ;
    ANTENNADIFFAREA 0.445500 ;
    PORT
      LAYER met2 ;
        RECT 87.490 0.000 87.770 4.000 ;
    END
  END output_ai[63]
  PIN output_ai[64]
    DIRECTION OUTPUT ;
    USE SIGNAL ;
    ANTENNADIFFAREA 0.445500 ;
    PORT
      LAYER met2 ;
        RECT 88.410 0.000 88.690 4.000 ;
    END
  END output_ai[64]
  PIN output_ai[65]
    DIRECTION OUTPUT ;
    USE SIGNAL ;
    ANTENNADIFFAREA 0.445500 ;
    PORT
      LAYER met2 ;
        RECT 89.330 0.000 89.610 4.000 ;
    END
  END output_ai[65]
  PIN output_ai[66]
    DIRECTION OUTPUT ;
    USE SIGNAL ;
    ANTENNADIFFAREA 0.445500 ;
    PORT
      LAYER met2 ;
        RECT 90.250 0.000 90.530 4.000 ;
    END
  END output_ai[66]
  PIN output_ai[67]
    DIRECTION OUTPUT ;
    USE SIGNAL ;
    ANTENNADIFFAREA 0.445500 ;
    PORT
      LAYER met2 ;
        RECT 91.170 0.000 91.450 4.000 ;
    END
  END output_ai[67]
  PIN output_ai[68]
    DIRECTION OUTPUT ;
    USE SIGNAL ;
    ANTENNADIFFAREA 0.445500 ;
    PORT
      LAYER met2 ;
        RECT 92.090 0.000 92.370 4.000 ;
    END
  END output_ai[68]
  PIN output_ai[69]
    DIRECTION OUTPUT ;
    USE SIGNAL ;
    ANTENNADIFFAREA 0.445500 ;
    PORT
      LAYER met2 ;
        RECT 93.010 0.000 93.290 4.000 ;
    END
  END output_ai[69]
  PIN output_ai[6]
    DIRECTION OUTPUT ;
    USE SIGNAL ;
    ANTENNADIFFAREA 0.445500 ;
    PORT
      LAYER met2 ;
        RECT 35.050 0.000 35.330 4.000 ;
    END
  END output_ai[6]
  PIN output_ai[70]
    DIRECTION OUTPUT ;
    USE SIGNAL ;
    ANTENNADIFFAREA 0.445500 ;
    PORT
      LAYER met2 ;
        RECT 93.930 0.000 94.210 4.000 ;
    END
  END output_ai[70]
  PIN output_ai[71]
    DIRECTION OUTPUT ;
    USE SIGNAL ;
    ANTENNADIFFAREA 0.445500 ;
    PORT
      LAYER met2 ;
        RECT 94.850 0.000 95.130 4.000 ;
    END
  END output_ai[71]
  PIN output_ai[72]
    DIRECTION OUTPUT ;
    USE SIGNAL ;
    ANTENNADIFFAREA 0.445500 ;
    PORT
      LAYER met2 ;
        RECT 95.770 0.000 96.050 4.000 ;
    END
  END output_ai[72]
  PIN output_ai[73]
    DIRECTION OUTPUT ;
    USE SIGNAL ;
    ANTENNADIFFAREA 0.445500 ;
    PORT
      LAYER met2 ;
        RECT 96.690 0.000 96.970 4.000 ;
    END
  END output_ai[73]
  PIN output_ai[74]
    DIRECTION OUTPUT ;
    USE SIGNAL ;
    ANTENNADIFFAREA 0.445500 ;
    PORT
      LAYER met2 ;
        RECT 97.610 0.000 97.890 4.000 ;
    END
  END output_ai[74]
  PIN output_ai[75]
    DIRECTION OUTPUT ;
    USE SIGNAL ;
    ANTENNADIFFAREA 0.445500 ;
    PORT
      LAYER met2 ;
        RECT 98.530 0.000 98.810 4.000 ;
    END
  END output_ai[75]
  PIN output_ai[76]
    DIRECTION OUTPUT ;
    USE SIGNAL ;
    ANTENNADIFFAREA 0.445500 ;
    PORT
      LAYER met2 ;
        RECT 99.450 0.000 99.730 4.000 ;
    END
  END output_ai[76]
  PIN output_ai[77]
    DIRECTION OUTPUT ;
    USE SIGNAL ;
    ANTENNADIFFAREA 0.445500 ;
    PORT
      LAYER met2 ;
        RECT 100.370 0.000 100.650 4.000 ;
    END
  END output_ai[77]
  PIN output_ai[78]
    DIRECTION OUTPUT ;
    USE SIGNAL ;
    ANTENNADIFFAREA 0.445500 ;
    PORT
      LAYER met2 ;
        RECT 101.290 0.000 101.570 4.000 ;
    END
  END output_ai[78]
  PIN output_ai[79]
    DIRECTION OUTPUT ;
    USE SIGNAL ;
    ANTENNADIFFAREA 0.445500 ;
    PORT
      LAYER met2 ;
        RECT 102.210 0.000 102.490 4.000 ;
    END
  END output_ai[79]
  PIN output_ai[7]
    DIRECTION OUTPUT ;
    USE SIGNAL ;
    ANTENNADIFFAREA 0.445500 ;
    PORT
      LAYER met2 ;
        RECT 35.970 0.000 36.250 4.000 ;
    END
  END output_ai[7]
  PIN output_ai[80]
    DIRECTION OUTPUT ;
    USE SIGNAL ;
    ANTENNADIFFAREA 0.445500 ;
    PORT
      LAYER met2 ;
        RECT 103.130 0.000 103.410 4.000 ;
    END
  END output_ai[80]
  PIN output_ai[81]
    DIRECTION OUTPUT ;
    USE SIGNAL ;
    ANTENNADIFFAREA 0.445500 ;
    PORT
      LAYER met2 ;
        RECT 104.050 0.000 104.330 4.000 ;
    END
  END output_ai[81]
  PIN output_ai[82]
    DIRECTION OUTPUT ;
    USE SIGNAL ;
    ANTENNADIFFAREA 0.445500 ;
    PORT
      LAYER met2 ;
        RECT 104.970 0.000 105.250 4.000 ;
    END
  END output_ai[82]
  PIN output_ai[83]
    DIRECTION OUTPUT ;
    USE SIGNAL ;
    ANTENNADIFFAREA 0.445500 ;
    PORT
      LAYER met2 ;
        RECT 105.890 0.000 106.170 4.000 ;
    END
  END output_ai[83]
  PIN output_ai[84]
    DIRECTION OUTPUT ;
    USE SIGNAL ;
    ANTENNADIFFAREA 0.445500 ;
    PORT
      LAYER met2 ;
        RECT 106.810 0.000 107.090 4.000 ;
    END
  END output_ai[84]
  PIN output_ai[85]
    DIRECTION OUTPUT ;
    USE SIGNAL ;
    ANTENNADIFFAREA 0.445500 ;
    PORT
      LAYER met2 ;
        RECT 107.730 0.000 108.010 4.000 ;
    END
  END output_ai[85]
  PIN output_ai[86]
    DIRECTION OUTPUT ;
    USE SIGNAL ;
    ANTENNADIFFAREA 0.445500 ;
    PORT
      LAYER met2 ;
        RECT 108.650 0.000 108.930 4.000 ;
    END
  END output_ai[86]
  PIN output_ai[87]
    DIRECTION OUTPUT ;
    USE SIGNAL ;
    ANTENNADIFFAREA 0.445500 ;
    PORT
      LAYER met2 ;
        RECT 109.570 0.000 109.850 4.000 ;
    END
  END output_ai[87]
  PIN output_ai[88]
    DIRECTION OUTPUT ;
    USE SIGNAL ;
    ANTENNADIFFAREA 0.445500 ;
    PORT
      LAYER met2 ;
        RECT 110.490 0.000 110.770 4.000 ;
    END
  END output_ai[88]
  PIN output_ai[89]
    DIRECTION OUTPUT ;
    USE SIGNAL ;
    ANTENNADIFFAREA 0.445500 ;
    PORT
      LAYER met2 ;
        RECT 111.410 0.000 111.690 4.000 ;
    END
  END output_ai[89]
  PIN output_ai[8]
    DIRECTION OUTPUT ;
    USE SIGNAL ;
    ANTENNADIFFAREA 0.445500 ;
    PORT
      LAYER met2 ;
        RECT 36.890 0.000 37.170 4.000 ;
    END
  END output_ai[8]
  PIN output_ai[90]
    DIRECTION OUTPUT ;
    USE SIGNAL ;
    ANTENNADIFFAREA 0.445500 ;
    PORT
      LAYER met2 ;
        RECT 112.330 0.000 112.610 4.000 ;
    END
  END output_ai[90]
  PIN output_ai[91]
    DIRECTION OUTPUT ;
    USE SIGNAL ;
    ANTENNADIFFAREA 0.445500 ;
    PORT
      LAYER met2 ;
        RECT 113.250 0.000 113.530 4.000 ;
    END
  END output_ai[91]
  PIN output_ai[92]
    DIRECTION OUTPUT ;
    USE SIGNAL ;
    ANTENNADIFFAREA 0.445500 ;
    PORT
      LAYER met2 ;
        RECT 114.170 0.000 114.450 4.000 ;
    END
  END output_ai[92]
  PIN output_ai[93]
    DIRECTION OUTPUT ;
    USE SIGNAL ;
    ANTENNADIFFAREA 0.445500 ;
    PORT
      LAYER met2 ;
        RECT 115.090 0.000 115.370 4.000 ;
    END
  END output_ai[93]
  PIN output_ai[94]
    DIRECTION OUTPUT ;
    USE SIGNAL ;
    ANTENNADIFFAREA 0.445500 ;
    PORT
      LAYER met2 ;
        RECT 116.010 0.000 116.290 4.000 ;
    END
  END output_ai[94]
  PIN output_ai[95]
    DIRECTION OUTPUT ;
    USE SIGNAL ;
    ANTENNADIFFAREA 0.445500 ;
    PORT
      LAYER met2 ;
        RECT 116.930 0.000 117.210 4.000 ;
    END
  END output_ai[95]
  PIN output_ai[96]
    DIRECTION OUTPUT ;
    USE SIGNAL ;
    ANTENNADIFFAREA 0.445500 ;
    PORT
      LAYER met2 ;
        RECT 117.850 0.000 118.130 4.000 ;
    END
  END output_ai[96]
  PIN output_ai[97]
    DIRECTION OUTPUT ;
    USE SIGNAL ;
    ANTENNADIFFAREA 0.445500 ;
    PORT
      LAYER met2 ;
        RECT 118.770 0.000 119.050 4.000 ;
    END
  END output_ai[97]
  PIN output_ai[98]
    DIRECTION OUTPUT ;
    USE SIGNAL ;
    ANTENNADIFFAREA 0.445500 ;
    PORT
      LAYER met2 ;
        RECT 119.690 0.000 119.970 4.000 ;
    END
  END output_ai[98]
  PIN output_ai[99]
    DIRECTION OUTPUT ;
    USE SIGNAL ;
    ANTENNADIFFAREA 0.445500 ;
    PORT
      LAYER met2 ;
        RECT 120.610 0.000 120.890 4.000 ;
    END
  END output_ai[99]
  PIN output_ai[9]
    DIRECTION OUTPUT ;
    USE SIGNAL ;
    ANTENNADIFFAREA 0.445500 ;
    PORT
      LAYER met2 ;
        RECT 37.810 0.000 38.090 4.000 ;
    END
  END output_ai[9]
  PIN reset
    DIRECTION INPUT ;
    USE SIGNAL ;
    ANTENNAGATEAREA 0.196500 ;
    PORT
      LAYER met3 ;
        RECT 0.000 144.200 4.000 144.800 ;
    END
  END reset
  OBS
      LAYER li1 ;
        RECT 5.520 10.795 273.700 277.525 ;
      LAYER met1 ;
        RECT 5.520 5.820 273.700 278.420 ;
      LAYER met2 ;
        RECT 6.990 285.935 11.310 286.215 ;
        RECT 12.150 285.935 28.330 286.215 ;
        RECT 29.170 285.935 45.350 286.215 ;
        RECT 46.190 285.935 62.370 286.215 ;
        RECT 63.210 285.935 79.390 286.215 ;
        RECT 80.230 285.935 96.410 286.215 ;
        RECT 97.250 285.935 113.430 286.215 ;
        RECT 114.270 285.935 130.450 286.215 ;
        RECT 131.290 285.935 147.470 286.215 ;
        RECT 148.310 285.935 164.490 286.215 ;
        RECT 165.330 285.935 181.510 286.215 ;
        RECT 182.350 285.935 198.530 286.215 ;
        RECT 199.370 285.935 215.550 286.215 ;
        RECT 216.390 285.935 232.570 286.215 ;
        RECT 233.410 285.935 249.590 286.215 ;
        RECT 250.430 285.935 266.610 286.215 ;
        RECT 267.450 285.935 269.460 286.215 ;
        RECT 6.990 4.280 269.460 285.935 ;
        RECT 6.990 3.555 29.250 4.280 ;
        RECT 30.090 3.555 30.170 4.280 ;
        RECT 31.010 3.555 31.090 4.280 ;
        RECT 31.930 3.555 32.010 4.280 ;
        RECT 32.850 3.555 32.930 4.280 ;
        RECT 33.770 3.555 33.850 4.280 ;
        RECT 34.690 3.555 34.770 4.280 ;
        RECT 35.610 3.555 35.690 4.280 ;
        RECT 36.530 3.555 36.610 4.280 ;
        RECT 37.450 3.555 37.530 4.280 ;
        RECT 38.370 3.555 38.450 4.280 ;
        RECT 39.290 3.555 39.370 4.280 ;
        RECT 40.210 3.555 40.290 4.280 ;
        RECT 41.130 3.555 41.210 4.280 ;
        RECT 42.050 3.555 42.130 4.280 ;
        RECT 42.970 3.555 43.050 4.280 ;
        RECT 43.890 3.555 43.970 4.280 ;
        RECT 44.810 3.555 44.890 4.280 ;
        RECT 45.730 3.555 45.810 4.280 ;
        RECT 46.650 3.555 46.730 4.280 ;
        RECT 47.570 3.555 47.650 4.280 ;
        RECT 48.490 3.555 48.570 4.280 ;
        RECT 49.410 3.555 49.490 4.280 ;
        RECT 50.330 3.555 50.410 4.280 ;
        RECT 51.250 3.555 51.330 4.280 ;
        RECT 52.170 3.555 52.250 4.280 ;
        RECT 53.090 3.555 53.170 4.280 ;
        RECT 54.010 3.555 54.090 4.280 ;
        RECT 54.930 3.555 55.010 4.280 ;
        RECT 55.850 3.555 55.930 4.280 ;
        RECT 56.770 3.555 56.850 4.280 ;
        RECT 57.690 3.555 57.770 4.280 ;
        RECT 58.610 3.555 58.690 4.280 ;
        RECT 59.530 3.555 59.610 4.280 ;
        RECT 60.450 3.555 60.530 4.280 ;
        RECT 61.370 3.555 61.450 4.280 ;
        RECT 62.290 3.555 62.370 4.280 ;
        RECT 63.210 3.555 63.290 4.280 ;
        RECT 64.130 3.555 64.210 4.280 ;
        RECT 65.050 3.555 65.130 4.280 ;
        RECT 65.970 3.555 66.050 4.280 ;
        RECT 66.890 3.555 66.970 4.280 ;
        RECT 67.810 3.555 67.890 4.280 ;
        RECT 68.730 3.555 68.810 4.280 ;
        RECT 69.650 3.555 69.730 4.280 ;
        RECT 70.570 3.555 70.650 4.280 ;
        RECT 71.490 3.555 71.570 4.280 ;
        RECT 72.410 3.555 72.490 4.280 ;
        RECT 73.330 3.555 73.410 4.280 ;
        RECT 74.250 3.555 74.330 4.280 ;
        RECT 75.170 3.555 75.250 4.280 ;
        RECT 76.090 3.555 76.170 4.280 ;
        RECT 77.010 3.555 77.090 4.280 ;
        RECT 77.930 3.555 78.010 4.280 ;
        RECT 78.850 3.555 78.930 4.280 ;
        RECT 79.770 3.555 79.850 4.280 ;
        RECT 80.690 3.555 80.770 4.280 ;
        RECT 81.610 3.555 81.690 4.280 ;
        RECT 82.530 3.555 82.610 4.280 ;
        RECT 83.450 3.555 83.530 4.280 ;
        RECT 84.370 3.555 84.450 4.280 ;
        RECT 85.290 3.555 85.370 4.280 ;
        RECT 86.210 3.555 86.290 4.280 ;
        RECT 87.130 3.555 87.210 4.280 ;
        RECT 88.050 3.555 88.130 4.280 ;
        RECT 88.970 3.555 89.050 4.280 ;
        RECT 89.890 3.555 89.970 4.280 ;
        RECT 90.810 3.555 90.890 4.280 ;
        RECT 91.730 3.555 91.810 4.280 ;
        RECT 92.650 3.555 92.730 4.280 ;
        RECT 93.570 3.555 93.650 4.280 ;
        RECT 94.490 3.555 94.570 4.280 ;
        RECT 95.410 3.555 95.490 4.280 ;
        RECT 96.330 3.555 96.410 4.280 ;
        RECT 97.250 3.555 97.330 4.280 ;
        RECT 98.170 3.555 98.250 4.280 ;
        RECT 99.090 3.555 99.170 4.280 ;
        RECT 100.010 3.555 100.090 4.280 ;
        RECT 100.930 3.555 101.010 4.280 ;
        RECT 101.850 3.555 101.930 4.280 ;
        RECT 102.770 3.555 102.850 4.280 ;
        RECT 103.690 3.555 103.770 4.280 ;
        RECT 104.610 3.555 104.690 4.280 ;
        RECT 105.530 3.555 105.610 4.280 ;
        RECT 106.450 3.555 106.530 4.280 ;
        RECT 107.370 3.555 107.450 4.280 ;
        RECT 108.290 3.555 108.370 4.280 ;
        RECT 109.210 3.555 109.290 4.280 ;
        RECT 110.130 3.555 110.210 4.280 ;
        RECT 111.050 3.555 111.130 4.280 ;
        RECT 111.970 3.555 112.050 4.280 ;
        RECT 112.890 3.555 112.970 4.280 ;
        RECT 113.810 3.555 113.890 4.280 ;
        RECT 114.730 3.555 114.810 4.280 ;
        RECT 115.650 3.555 115.730 4.280 ;
        RECT 116.570 3.555 116.650 4.280 ;
        RECT 117.490 3.555 117.570 4.280 ;
        RECT 118.410 3.555 118.490 4.280 ;
        RECT 119.330 3.555 119.410 4.280 ;
        RECT 120.250 3.555 120.330 4.280 ;
        RECT 121.170 3.555 121.250 4.280 ;
        RECT 122.090 3.555 122.170 4.280 ;
        RECT 123.010 3.555 123.090 4.280 ;
        RECT 123.930 3.555 124.010 4.280 ;
        RECT 124.850 3.555 124.930 4.280 ;
        RECT 125.770 3.555 125.850 4.280 ;
        RECT 126.690 3.555 126.770 4.280 ;
        RECT 127.610 3.555 127.690 4.280 ;
        RECT 128.530 3.555 128.610 4.280 ;
        RECT 129.450 3.555 129.530 4.280 ;
        RECT 130.370 3.555 130.450 4.280 ;
        RECT 131.290 3.555 131.370 4.280 ;
        RECT 132.210 3.555 132.290 4.280 ;
        RECT 133.130 3.555 133.210 4.280 ;
        RECT 134.050 3.555 134.130 4.280 ;
        RECT 134.970 3.555 135.050 4.280 ;
        RECT 135.890 3.555 135.970 4.280 ;
        RECT 136.810 3.555 136.890 4.280 ;
        RECT 137.730 3.555 137.810 4.280 ;
        RECT 138.650 3.555 138.730 4.280 ;
        RECT 139.570 3.555 139.650 4.280 ;
        RECT 140.490 3.555 140.570 4.280 ;
        RECT 141.410 3.555 141.490 4.280 ;
        RECT 142.330 3.555 142.410 4.280 ;
        RECT 143.250 3.555 143.330 4.280 ;
        RECT 144.170 3.555 144.250 4.280 ;
        RECT 145.090 3.555 145.170 4.280 ;
        RECT 146.010 3.555 146.090 4.280 ;
        RECT 146.930 3.555 147.010 4.280 ;
        RECT 147.850 3.555 147.930 4.280 ;
        RECT 148.770 3.555 148.850 4.280 ;
        RECT 149.690 3.555 149.770 4.280 ;
        RECT 150.610 3.555 150.690 4.280 ;
        RECT 151.530 3.555 151.610 4.280 ;
        RECT 152.450 3.555 152.530 4.280 ;
        RECT 153.370 3.555 153.450 4.280 ;
        RECT 154.290 3.555 154.370 4.280 ;
        RECT 155.210 3.555 155.290 4.280 ;
        RECT 156.130 3.555 156.210 4.280 ;
        RECT 157.050 3.555 157.130 4.280 ;
        RECT 157.970 3.555 158.050 4.280 ;
        RECT 158.890 3.555 158.970 4.280 ;
        RECT 159.810 3.555 159.890 4.280 ;
        RECT 160.730 3.555 160.810 4.280 ;
        RECT 161.650 3.555 161.730 4.280 ;
        RECT 162.570 3.555 162.650 4.280 ;
        RECT 163.490 3.555 163.570 4.280 ;
        RECT 164.410 3.555 164.490 4.280 ;
        RECT 165.330 3.555 165.410 4.280 ;
        RECT 166.250 3.555 166.330 4.280 ;
        RECT 167.170 3.555 167.250 4.280 ;
        RECT 168.090 3.555 168.170 4.280 ;
        RECT 169.010 3.555 169.090 4.280 ;
        RECT 169.930 3.555 170.010 4.280 ;
        RECT 170.850 3.555 170.930 4.280 ;
        RECT 171.770 3.555 171.850 4.280 ;
        RECT 172.690 3.555 172.770 4.280 ;
        RECT 173.610 3.555 173.690 4.280 ;
        RECT 174.530 3.555 174.610 4.280 ;
        RECT 175.450 3.555 175.530 4.280 ;
        RECT 176.370 3.555 176.450 4.280 ;
        RECT 177.290 3.555 177.370 4.280 ;
        RECT 178.210 3.555 178.290 4.280 ;
        RECT 179.130 3.555 179.210 4.280 ;
        RECT 180.050 3.555 180.130 4.280 ;
        RECT 180.970 3.555 181.050 4.280 ;
        RECT 181.890 3.555 181.970 4.280 ;
        RECT 182.810 3.555 182.890 4.280 ;
        RECT 183.730 3.555 183.810 4.280 ;
        RECT 184.650 3.555 184.730 4.280 ;
        RECT 185.570 3.555 185.650 4.280 ;
        RECT 186.490 3.555 186.570 4.280 ;
        RECT 187.410 3.555 187.490 4.280 ;
        RECT 188.330 3.555 188.410 4.280 ;
        RECT 189.250 3.555 189.330 4.280 ;
        RECT 190.170 3.555 190.250 4.280 ;
        RECT 191.090 3.555 191.170 4.280 ;
        RECT 192.010 3.555 192.090 4.280 ;
        RECT 192.930 3.555 193.010 4.280 ;
        RECT 193.850 3.555 193.930 4.280 ;
        RECT 194.770 3.555 194.850 4.280 ;
        RECT 195.690 3.555 195.770 4.280 ;
        RECT 196.610 3.555 196.690 4.280 ;
        RECT 197.530 3.555 197.610 4.280 ;
        RECT 198.450 3.555 198.530 4.280 ;
        RECT 199.370 3.555 199.450 4.280 ;
        RECT 200.290 3.555 200.370 4.280 ;
        RECT 201.210 3.555 201.290 4.280 ;
        RECT 202.130 3.555 202.210 4.280 ;
        RECT 203.050 3.555 203.130 4.280 ;
        RECT 203.970 3.555 204.050 4.280 ;
        RECT 204.890 3.555 204.970 4.280 ;
        RECT 205.810 3.555 205.890 4.280 ;
        RECT 206.730 3.555 206.810 4.280 ;
        RECT 207.650 3.555 207.730 4.280 ;
        RECT 208.570 3.555 208.650 4.280 ;
        RECT 209.490 3.555 209.570 4.280 ;
        RECT 210.410 3.555 210.490 4.280 ;
        RECT 211.330 3.555 211.410 4.280 ;
        RECT 212.250 3.555 212.330 4.280 ;
        RECT 213.170 3.555 213.250 4.280 ;
        RECT 214.090 3.555 214.170 4.280 ;
        RECT 215.010 3.555 215.090 4.280 ;
        RECT 215.930 3.555 216.010 4.280 ;
        RECT 216.850 3.555 216.930 4.280 ;
        RECT 217.770 3.555 217.850 4.280 ;
        RECT 218.690 3.555 218.770 4.280 ;
        RECT 219.610 3.555 219.690 4.280 ;
        RECT 220.530 3.555 220.610 4.280 ;
        RECT 221.450 3.555 221.530 4.280 ;
        RECT 222.370 3.555 222.450 4.280 ;
        RECT 223.290 3.555 223.370 4.280 ;
        RECT 224.210 3.555 224.290 4.280 ;
        RECT 225.130 3.555 225.210 4.280 ;
        RECT 226.050 3.555 226.130 4.280 ;
        RECT 226.970 3.555 227.050 4.280 ;
        RECT 227.890 3.555 227.970 4.280 ;
        RECT 228.810 3.555 228.890 4.280 ;
        RECT 229.730 3.555 229.810 4.280 ;
        RECT 230.650 3.555 230.730 4.280 ;
        RECT 231.570 3.555 231.650 4.280 ;
        RECT 232.490 3.555 232.570 4.280 ;
        RECT 233.410 3.555 233.490 4.280 ;
        RECT 234.330 3.555 234.410 4.280 ;
        RECT 235.250 3.555 235.330 4.280 ;
        RECT 236.170 3.555 236.250 4.280 ;
        RECT 237.090 3.555 237.170 4.280 ;
        RECT 238.010 3.555 238.090 4.280 ;
        RECT 238.930 3.555 239.010 4.280 ;
        RECT 239.850 3.555 239.930 4.280 ;
        RECT 240.770 3.555 240.850 4.280 ;
        RECT 241.690 3.555 241.770 4.280 ;
        RECT 242.610 3.555 242.690 4.280 ;
        RECT 243.530 3.555 243.610 4.280 ;
        RECT 244.450 3.555 244.530 4.280 ;
        RECT 245.370 3.555 245.450 4.280 ;
        RECT 246.290 3.555 246.370 4.280 ;
        RECT 247.210 3.555 247.290 4.280 ;
        RECT 248.130 3.555 248.210 4.280 ;
        RECT 249.050 3.555 249.130 4.280 ;
        RECT 249.970 3.555 269.460 4.280 ;
      LAYER met3 ;
        RECT 4.000 145.200 275.495 277.605 ;
        RECT 4.400 143.800 275.095 145.200 ;
        RECT 4.000 3.575 275.495 143.800 ;
      LAYER met4 ;
        RECT 29.735 10.240 174.240 145.345 ;
        RECT 176.640 10.240 177.540 145.345 ;
        RECT 179.940 10.240 248.105 145.345 ;
        RECT 29.735 3.575 248.105 10.240 ;
  END
END shifter
END LIBRARY

